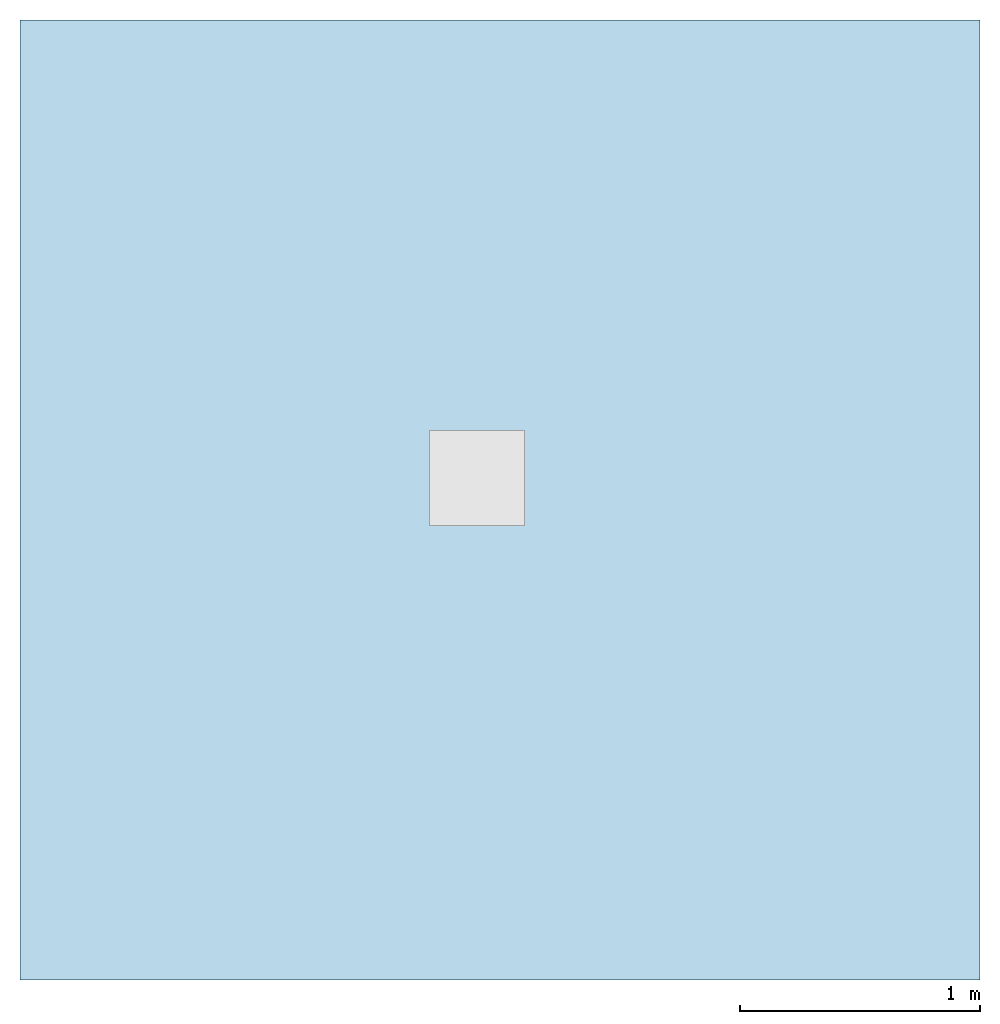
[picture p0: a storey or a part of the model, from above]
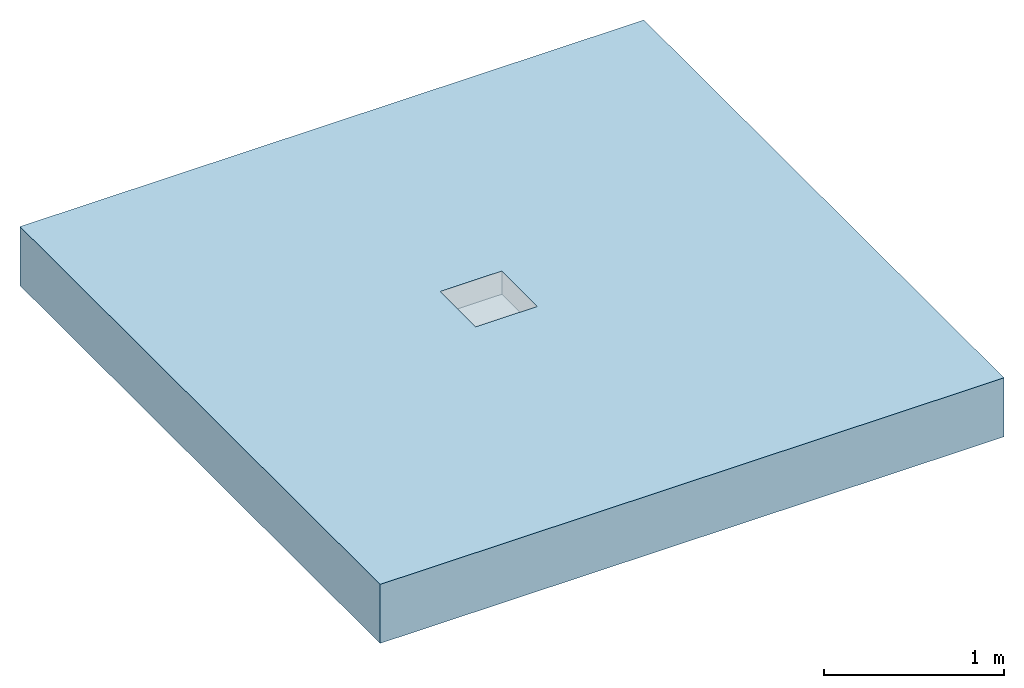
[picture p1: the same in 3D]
Properties of the parts of a building model (IFC2X3)

# File
Description: ViewDefinition [CoordinationView]
File name: Project Number
Time: 2014-06-06T10:55:40
Written by: The EXPRESS Data Manager Version 5.01.0100.02.64mod : 6 Jun 2012
Made in: 20130308_1515(x64) - Exporter 2014.0.2013.0308 - Default UI
Comment: STEP Physical File produced by: The EXPRESS Data Manager Version 5.01.0100.02.64mod : 6 Jun 2012 * Module: EDMstepFileFactory/EDMstandAlone * Creation date: Fri Jun 06 10:55:40 2014 * Host: IN-BLR-PC-0010 * Database: C:\Users\palleri\AppData\Local\Temp\{7D1091A5-F40D-4BBD-89F8-A0A742FCD9DC}\ifc * Database version: 5507 * Database creation date: Fri Jun 06 10:55:38 2014 * Schema: IFC2X3 * Model: DataRepository.ifc * Model creation date: Fri Jun 06 10:55:39 2014 * Header model: DataRepository.ifc_HeaderModel * Header model creation date: Fri Jun 06 10:55:39 2014 * EDMuser: sdai-user * EDMgroup: sdai-group * License ID and type: 5605 : Permanent license. Expiry date: * EDMstepFileFactory options: 020000

# IfcProject, Project Number
LongName: Project Name; Phase: Project Status

# IfcSite, Default
RefLatitude: 42, 21, 30, 344238; RefLongitude: -71, -3, -35, -194702; RefElevation: 0 mm

# IfcBuilding
Pset_BuildingCommon - NumberOfStoreys: 1
Other - Project Issue Date: Issue Date; Project Status: Project Status; Project Name: Project Name; Client Name: Owner; Project Address: ## Street City, State Zip; Project Number: Project Number

# IfcBuildingStorey, Level 1
LongName: Level 1; Elevation: 0 mm
Constraints - Elevation Base: Project Base Point; Elevation: 0 mm
Graphics - Color: 0; Line Weight: 1; Line Pattern: Center; Symbol: M_Level Head - Circle: M_Level Head - Circle; Symbol at End 2 Default: yes; Symbol at End 1 Default: no
Identity Data - Building Story: yes; Name: Level 1; Structural: no
Dimensions - Computation Height: 0 mm

# IfcFlowTerminal: 38801 - Access Frame - Adjustable Height - Invert Depth 75/105mm, ACO Freedeck Access Frame & Drain Duct (Accessories part 1) V1.27 - GS:38801 - Access Frame - Adjustable Height - Invert Depth 75/105mm:276243
In: Level 1
Material: Galvanized Steel
Dimensions - Grating End: -20 mm; Drain Duct End: -100 mm; Grating Start: 0 mm; Top Void Height Start: -105 mm; Base Height: 75 mm; Drainage Duct – Level below FFL: 30 mm; Access Frame Extension Position Height: 0 mm; Height for Adjustable Access Frame: 105 mm; Total Height: 159 mm; Top Void Height End: -55 mm
Other - Access Frame Extension Height: 75 mm; Access Frame Extension: yes; Adjustable Access Frame Position Height: 105 mm; Extension Removal Void: -2 mm; Fixed Access Frame Position Height: 105 mm; Drain Duct Vertical Height: 5000 mm; Access Frame Extension_Invert Depth 50mm: no; Access Frame Extension_Invert Depth 75mm: yes; Access Frame Adjustable Height: yes; Drain Duct: no; Grating: yes; Access Frame Fixed Height: no; Top void Size: 397 mm
Construction - 38687_Access Frame Extension_Galvanized Steel_Invert Depth 75mm: yes; 38685_Access Frame Extension_Galvanized Steel_Invert Depth 50mm: no; 36754_Access Grating_Mesh Grating_Galvanized Steel: yes
Constraints - Level: Level: Level 1; Moves With Nearby Elements: no
Phasing - Phase Created: New Construction
Identity Data - Mark: 14; Watermarked With: BIM Manager Premium Suite; Watermark2: This file is water marked and users are prohibited to reproduce, adapt, distribute this information; Watermarked By: www.acobd.com; Manufacturer: ACO Building Drainage; Fax: +44 (0)1462 851490; Website: www.acobd.com; E-mail Sales: abdcommercial@aco.co.uk; Address: ACO Business Centre, Caxton Road, Bedford, MK41 0LF; Watermark1: This file is the property of ACO Technologies PLC; Telephone: +44 (0)1462 816666; E-mail Technical: abdtechnical@aco.co.uk
Pset_ManufacturerTypeInformation - Manufacturer: ACO Building Drainage
General - NBS Specification: NBS Section R10 Gravity Rainwater Drainage Systems, Subsection 365; Price: POA - contact ACO; Product Type: Linear Deck Drainage System; Channel Material: Hot Dipped Galvanised Steel; Product Range: ACO Freedeck; Installation Guidelines: X:\Electronic Literature\ABD Electronic Literature\Roof and Balcony Drainage\ACO Freedeck Brochure.pdf; Maintenance Guidelines: X:\Electronic Literature\ABD Electronic Literature\Roof and Balcony Drainage\ACO Freedeck Brochure.pdf; Channel Recycled Material Content: 25 - 30 %; Channel Colour: Galvanised; Channel Recyclable: Fully recyclable; Load Class: A15; Dimensions (LxWxH): 400 x 400 x 75/105; Product Description: ACO Freedeck Access Frame - Adjustable; Product Standard: BS EN 1433:2002, CE marked; Product Code: 38801; Weight (Kg): 3.1kg
Model Properties - Access Frame Extension Product Code 38686: N/A; Access Frame Extension Product Code 38685: Load Class A15 - Access Frame Extension - Galvanized Steel - Invert Depth 50mm - 1.3kg; Access Frame Extension Product Code 38687: Load Class A15 - Access Frame Extension - Galvanized Steel - Invert Depth 75mm - 1.9kg; Access Frame Extension Product Code 38688: N/A; Access Grating Product Code 36760: N/A; Access Grating Product Code 36754: Load Class A15 - Mesh Grating - 14mm x 30mm Mesh - Galvanized Steel - 3.5kg
Materials and Finishes - Material: Galvanized Steel

# IfcOpeningElement: Recess (2)
In: Level 1
Constraints - Level: Level: Level 1; Related to Mass: no; Room Bounding: yes; Height Offset From Level: 0 mm
Phasing - Phase Created: New Construction
Dimensions - Volume: 6.37485 m3; Area: 16 m2; Perimeter: 16000 mm; Thickness: 400 mm
Structural - Enable Analytical Model: no; Structural: no
Materials and Finishes - Structural Material: Concrete, Broom Finish
Graphics - Coarse Scale Fill Color: 0
Construction - Function: Interior; Default Thickness: 400 mm
Analytical Properties - Roughness: 1; Heat Transfer Coefficient (U): 2.615; Absorptance: 0.1; Thermal mass: 604440; Thermal Resistance (R): 0.382409

# IfcSlab: Floor:Generic Floor - 400mm, Floor:Generic Floor - 400mm:193825
In: Level 1
PredefinedType: FLOOR; Material: Concrete, Broom Finish 400 mm
Constraints - Level: Level: Level 1; Related to Mass: no; Room Bounding: yes; Height Offset From Level: 0 mm
Phasing - Phase Created: New Construction
Dimensions - Volume: 6.37485 m3; Area: 16 m2; Perimeter: 16000 mm; Thickness: 400 mm
Structural - Enable Analytical Model: no; Structural: no
Pset_SlabCommon - Reference: Generic Floor - 400mm; IsExternal: no; LoadBearing: yes; ThermalTransmittance: 2.615 kg/K/s3
Materials and Finishes - Structural Material: Concrete, Broom Finish
Graphics - Coarse Scale Fill Color: 0
Construction - Function: Interior; Default Thickness: 400 mm
Analytical Properties - Roughness: 1; Heat Transfer Coefficient (U): 2.615; Absorptance: 0.1; Thermal mass: 604440; Thermal Resistance (R): 0.382409
